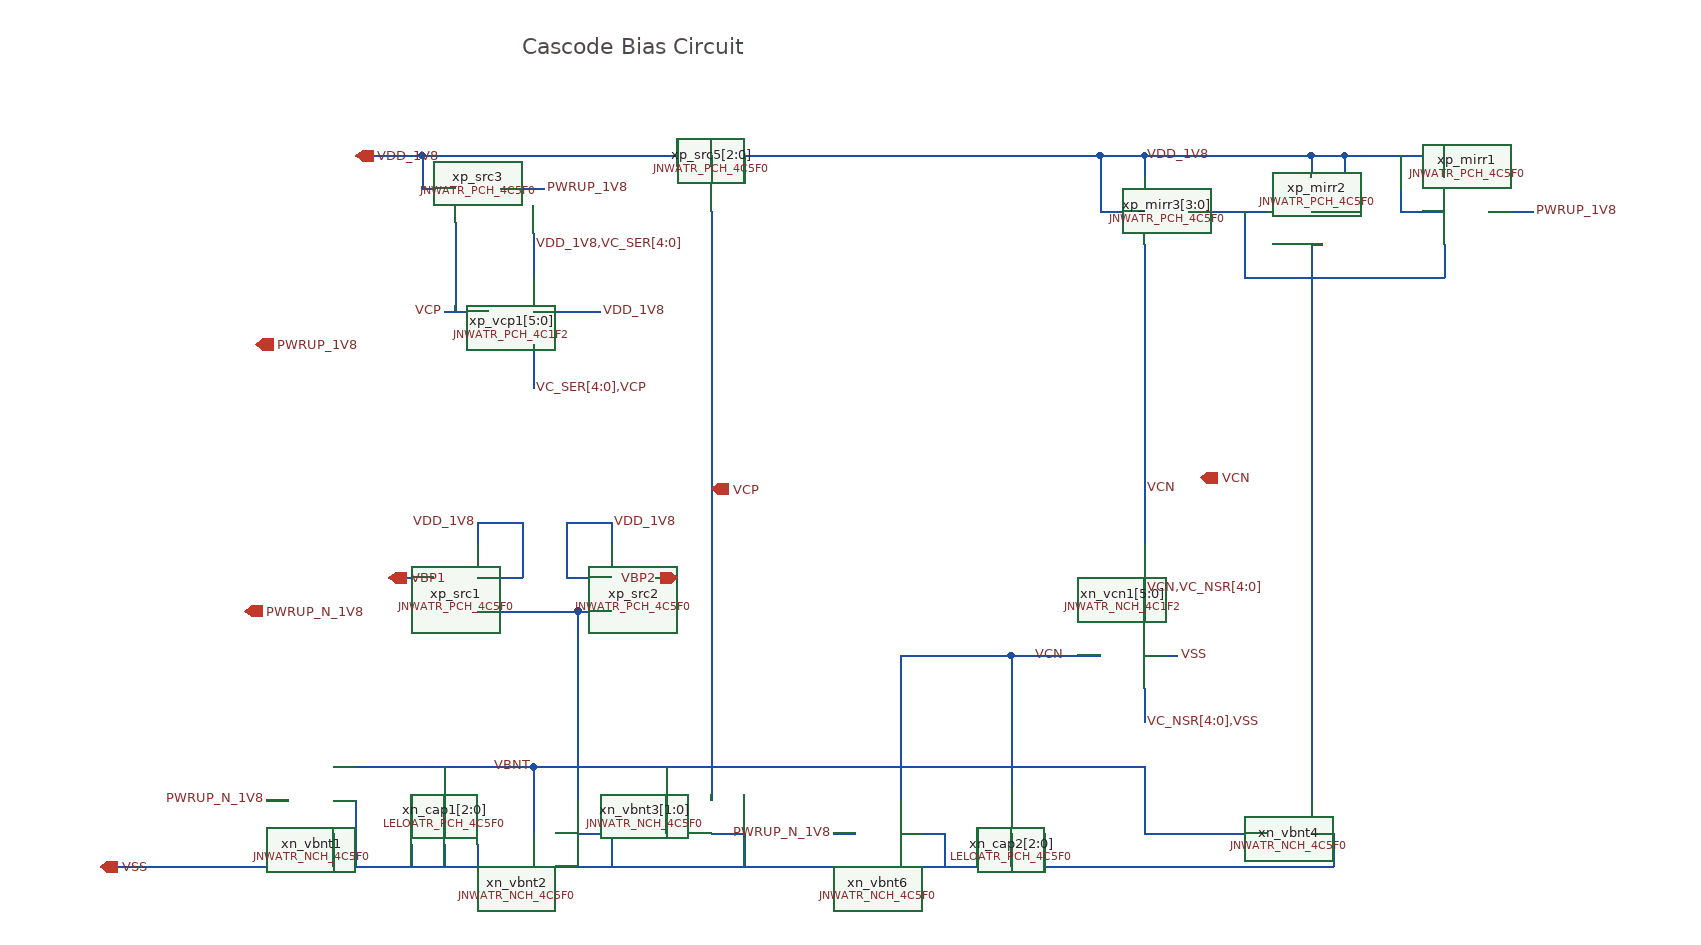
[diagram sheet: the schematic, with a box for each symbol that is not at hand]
v {xschem version=3.4.7 file_version=1.2}
G {}
K {}
V {}
S {}
E {}
T {Cascode Bias Circuit} 390 -1040 0 0 1 1 {}
N 400 -790 430 -790 {lab=VDD_1V8}
N 430 -790 460 -790 {lab=VDD_1V8}
N 320 -790 360 -790 {lab=VCP}
N 400 -860 400 -820 {lab=VDD_1V8,VC_SER[4:0]}
N 400 -760 400 -720 {lab=VC_SER[4:0],VCP}
N 240 -350 240 -290 {lab=VSS}
N 220 -350 240 -350 {lab=VSS}
N 220 -320 220 -290 {lab=VSS}
N 160 -350 180 -350 {lab=PWRUP_N_1V8}
N 950 -550 950 -510 {lab=VCN,VC_NSR[4:0]}
N 880 -480 910 -480 {lab=VCN}
N 950 -480 980 -480 {lab=VSS}
N 950 -450 950 -420 {lab=VC_NSR[4:0],VSS}
N 270 -550 310 -550 {lab=VBP1}
N 350 -550 390 -550 {lab=VDD_1V8}
N 390 -600 390 -550 {lab=VDD_1V8}
N 350 -600 390 -600 {lab=VDD_1V8}
N 350 -600 350 -580 {lab=VDD_1V8}
N 440 -320 470 -320 {lab=VSS}
N 470 -320 470 -290 {lab=VSS}
N 440 -290 470 -290 {lab=VSS}
N 440 -520 440 -350 {lab=VBNT}
N 400 -380 400 -320 {lab=VBNT}
N 400 -380 440 -380 {lab=VBNT}
N 910 -880 950 -880 {lab=VDD_1V8}
N 910 -930 910 -880 {lab=VDD_1V8}
N 910 -930 950 -930 {lab=VDD_1V8}
N 950 -930 950 -910 {lab=VDD_1V8}
N 950 -850 950 -680 {lab=VCN}
N 950 -680 950 -580 {lab=VCN}
N 220 -380 400 -380 {lab=VBNT}
N 560 -320 590 -320 {lab=VSS}
N 590 -320 590 -290 {lab=VSS}
N 440 -380 590 -380 {lab=VBNT}
N 430 -550 470 -550 {lab=VDD_1V8}
N 430 -600 430 -550 {lab=VDD_1V8}
N 430 -600 470 -600 {lab=VDD_1V8}
N 470 -600 470 -580 {lab=VDD_1V8}
N 350 -520 440 -520 {lab=VBNT}
N 990 -880 1060 -880 {lab=#net1}
N 950 -930 1100 -930 {lab=VDD_1V8}
N 1100 -930 1100 -910 {lab=VDD_1V8}
N 1100 -880 1130 -880 {lab=VDD_1V8}
N 1130 -930 1130 -880 {lab=VDD_1V8}
N 1100 -930 1130 -930 {lab=VDD_1V8}
N 1100 -850 1100 -350 {lab=#net1}
N 1100 -850 1110 -850 {lab=#net1}
N 1100 -320 1120 -320 {lab=VSS}
N 1120 -320 1120 -290 {lab=VSS}
N 950 -380 950 -320 {lab=VBNT}
N 1040 -880 1040 -820 {lab=#net1}
N 1040 -820 1100 -820 {lab=#net1}
N 440 -520 470 -520 {lab=VBNT}
N 950 -320 1060 -320 {lab=VBNT}
N 590 -380 950 -380 {lab=VBNT}
N 1220 -850 1220 -820 {lab=#net1}
N 1100 -820 1220 -820 {lab=#net1}
N 1220 -930 1220 -910 {lab=VDD_1V8}
N 1130 -930 1220 -930 {lab=VDD_1V8}
N 1180 -880 1220 -880 {lab=VDD_1V8}
N 1180 -930 1180 -880 {lab=VDD_1V8}
N 1260 -880 1300 -880 {lab=PWRUP_1V8}
N 300 -900 330 -900 {lab=VDD_1V8}
N 300 -930 300 -900 {lab=VDD_1V8}
N 300 -930 330 -930 {lab=VDD_1V8}
N 370 -900 410 -900 {lab=PWRUP_1V8}
N 670 -320 690 -320 {lab=PWRUP_N_1V8}
N 600 -930 910 -930 {lab=VDD_1V8}
N 590 -930 590 -920 {lab=VDD_1V8}
N 560 -930 560 -920 {lab=VDD_1V8}
N 560 -880 560 -680 {lab=VCP}
N 290 -310 290 -290 {lab=VSS}
N 320 -310 320 -290 {lab=VSS}
N 350 -310 350 -290 {lab=VSS}
N 320 -380 320 -350 {lab=VBNT}
N 240 -930 300 -930 {lab=VDD_1V8}
N 330 -930 540 -930 {lab=VDD_1V8}
N 180 -290 1120 -290 {lab=VSS}
N 10 -290 180 -290 {lab=VSS}
N 510 -550 530 -550 {lab=VBP2}
N 560 -680 560 -350 {lab=VCP}
N 800 -320 800 -290 {lab=VSS}
N 830 -320 830 -290 {lab=VSS}
N 860 -320 860 -290 {lab=VSS}
N 830 -480 830 -360 {lab=VCN}
N 830 -480 880 -480 {lab=VCN}
N 330 -870 330 -790 {lab=VCP}
N 520 -370 520 -320 {lab=VBNT}
N 730 -320 770 -320 {lab=VSS}
N 770 -320 770 -290 {lab=VSS}
N 730 -480 730 -350 {lab=VCN}
N 730 -480 830 -480 {lab=VCN}
N 520 -380 520 -370 {lab=VBNT}
N 540 -930 600 -930 {lab=VDD_1V8}
N 530 -930 530 -920 {lab=VDD_1V8}
C {JNW_ATR_SKY130A/JNWATR_PCH_4C1F2.sym} 360 -790 0 0 {name=xp_vcp1[5:0]}
C {devices/lab_wire.sym} 460 -790 0 1 {name=p40 sig_type=std_logic lab=VDD_1V8}
C {devices/lab_wire.sym} 400 -850 0 1 {name=p41 sig_type=std_logic lab=VDD_1V8,VC_SER[4:0]}
C {devices/lab_wire.sym} 400 -720 0 1 {name=p42 sig_type=std_logic lab=VC_SER[4:0],VCP}
C {JNW_ATR_SKY130A/JNWATR_NCH_4C1F2.sym} 910 -480 0 0 {name=xn_vcn1[5:0]}
C {JNW_ATR_SKY130A/JNWATR_NCH_4C5F0.sym} 180 -350 0 0 {name=xn_vbnt1}
C {devices/lab_wire.sym} 880 -480 0 0 {name=p46 sig_type=std_logic lab=VCN}
C {devices/lab_wire.sym} 980 -480 0 1 {name=p47 sig_type=std_logic lab=VSS}
C {devices/lab_wire.sym} 950 -540 0 1 {name=p48 sig_type=std_logic lab=VCN,VC_NSR[4:0]}
C {devices/lab_wire.sym} 950 -420 0 1 {name=p49 sig_type=std_logic lab=VC_NSR[4:0],VSS}
C {devices/opin.sym} 560 -630 0 0 {name=p53 lab=VCP}
C {JNW_ATR_SKY130A/JNWATR_PCH_4C5F0.sym} 310 -550 0 0 {name=xp_src1}
C {devices/lab_wire.sym} 350 -600 0 0 {name=p59 sig_type=std_logic lab=VDD_1V8}
C {JNW_ATR_SKY130A/JNWATR_NCH_4C5F0.sym} 400 -320 0 0 {name=xn_vbnt2}
C {devices/lab_wire.sym} 400 -380 0 0 {name=p60 sig_type=std_logic lab=VBNT}
C {devices/lab_wire.sym} 320 -790 0 0 {name=p3 sig_type=std_logic lab=VCP
}
C {JNW_ATR_SKY130A/JNWATR_PCH_4C5F0.sym} 990 -880 0 1 {name=xp_mirr3[3:0]}
C {devices/lab_wire.sym} 950 -930 0 1 {name=p32 sig_type=std_logic lab=VDD_1V8}
C {devices/lab_wire.sym} 950 -630 0 1 {name=p35 sig_type=std_logic lab=VCN}
C {JNW_ATR_SKY130A/JNWATR_NCH_4C5F0.sym} 520 -320 0 0 {name=xn_vbnt3[1:0]}
C {JNW_ATR_SKY130A/JNWATR_PCH_4C5F0.sym} 510 -550 0 1 {name=xp_src2}
C {devices/lab_wire.sym} 470 -600 0 1 {name=p55 sig_type=std_logic lab=VDD_1V8}
C {JNW_ATR_SKY130A/JNWATR_PCH_4C5F0.sym} 1060 -880 0 0 {name=xp_mirr2}
C {JNW_ATR_SKY130A/JNWATR_NCH_4C5F0.sym} 1060 -320 0 0 {name=xn_vbnt4}
C {JNW_ATR_SKY130A/JNWATR_PCH_4C5F0.sym} 1260 -880 0 1 {name=xp_mirr1}
C {devices/lab_wire.sym} 1300 -880 0 1 {name=p67 sig_type=std_logic lab=PWRUP_1V8
}
C {JNW_ATR_SKY130A/JNWATR_PCH_4C5F0.sym} 370 -900 0 1 {name=xp_src3}
C {devices/lab_wire.sym} 410 -900 0 1 {name=p68 sig_type=std_logic lab=PWRUP_1V8
}
C {JNW_ATR_SKY130A/JNWATR_NCH_4C5F0.sym} 690 -320 0 0 {name=xn_vbnt6}
C {devices/lab_wire.sym} 670 -320 2 1 {name=p69 sig_type=std_logic lab=PWRUP_N_1V8}
C {JNW_ATR_SKY130A/JNWATR_PCH_4C5F0.sym} 560 -880 3 0 {name=xp_src5[2:0]}
C {LELO_ATR_SKY130A/LELOATR_PCH_4C5F0.sym} 830 -360 1 0 {name=xn_cap2[2:0]}
C {LELO_ATR_SKY130A/LELOATR_PCH_4C5F0.sym} 320 -350 1 0 {name=xn_cap1[2:0]}
C {devices/ipin.sym} 240 -930 2 1 {name=p4 lab=VDD_1V8}
C {devices/ipin.sym} 10 -290 2 1 {name=p5 lab=VSS}
C {devices/ipin.sym} 140 -520 2 1 {name=p9 lab=PWRUP_N_1V8}
C {devices/ipin.sym} 150 -760 2 1 {name=p10 lab=PWRUP_1V8}
C {devices/opin.sym} 1000 -640 0 0 {name=p1 lab=VCN}
C {devices/lab_wire.sym} 160 -350 2 1 {name=p2 sig_type=std_logic lab=PWRUP_N_1V8}
C {devices/ipin.sym} 270 -550 2 1 {name=p6 lab=VBP1}
C {devices/ipin.sym} 530 -550 2 0 {name=p7 lab=VBP2}
